VERSION 5.7 ;
  NOWIREEXTENSIONATPIN ON ;
  DIVIDERCHAR "/" ;
  BUSBITCHARS "[]" ;
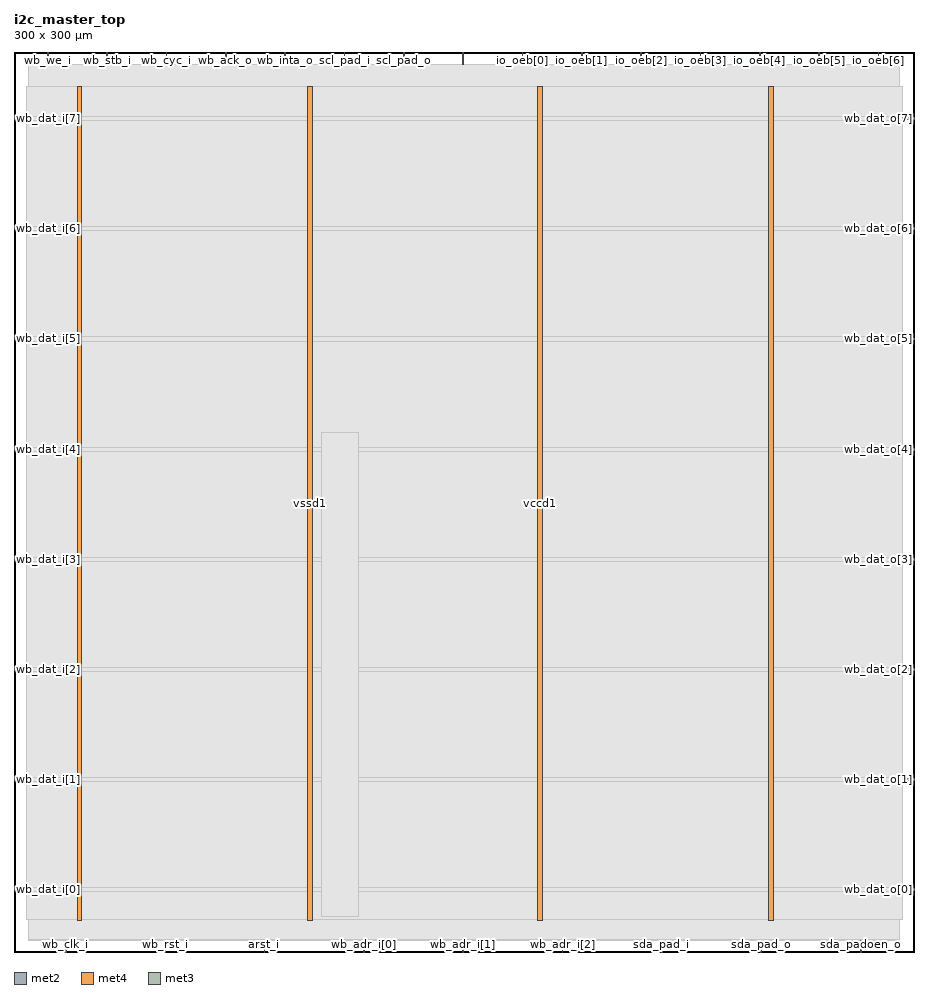
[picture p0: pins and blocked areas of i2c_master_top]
MACRO i2c_master_top
  CLASS BLOCK ;
  FOREIGN i2c_master_top ;
  ORIGIN 0.000 0.000 ;
  SIZE 300.000 BY 300.000 ;
  PIN arst_i
    DIRECTION INPUT ;
    USE SIGNAL ;
    ANTENNAGATEAREA 0.852000 ;
    PORT
      LAYER met2 ;
        RECT 83.350 0.000 83.630 4.000 ;
    END
  END arst_i
  PIN io_oeb[0]
    DIRECTION OUTPUT TRISTATE ;
    USE SIGNAL ;
    PORT
      LAYER met2 ;
        RECT 169.370 296.000 169.650 300.000 ;
    END
  END io_oeb[0]
  PIN io_oeb[1]
    DIRECTION OUTPUT TRISTATE ;
    USE SIGNAL ;
    PORT
      LAYER met2 ;
        RECT 189.150 296.000 189.430 300.000 ;
    END
  END io_oeb[1]
  PIN io_oeb[2]
    DIRECTION OUTPUT TRISTATE ;
    USE SIGNAL ;
    PORT
      LAYER met2 ;
        RECT 208.930 296.000 209.210 300.000 ;
    END
  END io_oeb[2]
  PIN io_oeb[3]
    DIRECTION OUTPUT TRISTATE ;
    USE SIGNAL ;
    PORT
      LAYER met2 ;
        RECT 228.710 296.000 228.990 300.000 ;
    END
  END io_oeb[3]
  PIN io_oeb[4]
    DIRECTION OUTPUT TRISTATE ;
    USE SIGNAL ;
    PORT
      LAYER met2 ;
        RECT 248.490 296.000 248.770 300.000 ;
    END
  END io_oeb[4]
  PIN io_oeb[5]
    DIRECTION OUTPUT TRISTATE ;
    USE SIGNAL ;
    PORT
      LAYER met2 ;
        RECT 268.270 296.000 268.550 300.000 ;
    END
  END io_oeb[5]
  PIN io_oeb[6]
    DIRECTION OUTPUT TRISTATE ;
    USE SIGNAL ;
    PORT
      LAYER met2 ;
        RECT 288.050 296.000 288.330 300.000 ;
    END
  END io_oeb[6]
  PIN scl_pad_i
    DIRECTION INPUT ;
    USE SIGNAL ;
    ANTENNAGATEAREA 0.196500 ;
    PORT
      LAYER met2 ;
        RECT 110.030 296.000 110.310 300.000 ;
    END
  END scl_pad_i
  PIN scl_pad_o
    DIRECTION OUTPUT TRISTATE ;
    USE SIGNAL ;
    PORT
      LAYER met2 ;
        RECT 129.810 296.000 130.090 300.000 ;
    END
  END scl_pad_o
  PIN scl_padoen_o
    DIRECTION OUTPUT TRISTATE ;
    USE SIGNAL ;
    ANTENNADIFFAREA 0.340600 ;
    PORT
      LAYER met2 ;
        RECT 149.590 296.000 149.870 300.000 ;
    END
  END scl_padoen_o
  PIN sda_pad_i
    DIRECTION INPUT ;
    USE SIGNAL ;
    ANTENNAGATEAREA 0.196500 ;
    PORT
      LAYER met2 ;
        RECT 215.830 0.000 216.110 4.000 ;
    END
  END sda_pad_i
  PIN sda_pad_o
    DIRECTION OUTPUT TRISTATE ;
    USE SIGNAL ;
    PORT
      LAYER met2 ;
        RECT 248.950 0.000 249.230 4.000 ;
    END
  END sda_pad_o
  PIN sda_padoen_o
    DIRECTION OUTPUT TRISTATE ;
    USE SIGNAL ;
    ANTENNADIFFAREA 0.340600 ;
    PORT
      LAYER met2 ;
        RECT 282.070 0.000 282.350 4.000 ;
    END
  END sda_padoen_o
  PIN vccd1
    DIRECTION INOUT ;
    USE POWER ;
    PORT
      LAYER met4 ;
        RECT 21.040 10.640 22.640 288.560 ;
    END
    PORT
      LAYER met4 ;
        RECT 174.640 10.640 176.240 288.560 ;
    END
  END vccd1
  PIN vssd1
    DIRECTION INOUT ;
    USE GROUND ;
    PORT
      LAYER met4 ;
        RECT 97.840 10.640 99.440 288.560 ;
    END
    PORT
      LAYER met4 ;
        RECT 251.440 10.640 253.040 288.560 ;
    END
  END vssd1
  PIN wb_ack_o
    DIRECTION OUTPUT TRISTATE ;
    USE SIGNAL ;
    ANTENNADIFFAREA 0.340600 ;
    PORT
      LAYER met2 ;
        RECT 70.470 296.000 70.750 300.000 ;
    END
  END wb_ack_o
  PIN wb_adr_i[0]
    DIRECTION INPUT ;
    USE SIGNAL ;
    ANTENNAGATEAREA 0.159000 ;
    PORT
      LAYER met2 ;
        RECT 116.470 0.000 116.750 4.000 ;
    END
  END wb_adr_i[0]
  PIN wb_adr_i[1]
    DIRECTION INPUT ;
    USE SIGNAL ;
    ANTENNAGATEAREA 0.213000 ;
    PORT
      LAYER met2 ;
        RECT 149.590 0.000 149.870 4.000 ;
    END
  END wb_adr_i[1]
  PIN wb_adr_i[2]
    DIRECTION INPUT ;
    USE SIGNAL ;
    ANTENNAGATEAREA 0.159000 ;
    PORT
      LAYER met2 ;
        RECT 182.710 0.000 182.990 4.000 ;
    END
  END wb_adr_i[2]
  PIN wb_clk_i
    DIRECTION INPUT ;
    USE SIGNAL ;
    ANTENNAGATEAREA 0.852000 ;
    PORT
      LAYER met2 ;
        RECT 17.110 0.000 17.390 4.000 ;
    END
  END wb_clk_i
  PIN wb_cyc_i
    DIRECTION INPUT ;
    USE SIGNAL ;
    ANTENNAGATEAREA 0.196500 ;
    PORT
      LAYER met2 ;
        RECT 50.690 296.000 50.970 300.000 ;
    END
  END wb_cyc_i
  PIN wb_dat_i[0]
    DIRECTION INPUT ;
    USE SIGNAL ;
    ANTENNAGATEAREA 0.159000 ;
    PORT
      LAYER met3 ;
        RECT 0.000 20.440 4.000 21.040 ;
    END
  END wb_dat_i[0]
  PIN wb_dat_i[1]
    DIRECTION INPUT ;
    USE SIGNAL ;
    ANTENNAGATEAREA 0.213000 ;
    PORT
      LAYER met3 ;
        RECT 0.000 57.160 4.000 57.760 ;
    END
  END wb_dat_i[1]
  PIN wb_dat_i[2]
    DIRECTION INPUT ;
    USE SIGNAL ;
    ANTENNAGATEAREA 0.213000 ;
    PORT
      LAYER met3 ;
        RECT 0.000 93.880 4.000 94.480 ;
    END
  END wb_dat_i[2]
  PIN wb_dat_i[3]
    DIRECTION INPUT ;
    USE SIGNAL ;
    ANTENNAGATEAREA 0.213000 ;
    PORT
      LAYER met3 ;
        RECT 0.000 130.600 4.000 131.200 ;
    END
  END wb_dat_i[3]
  PIN wb_dat_i[4]
    DIRECTION INPUT ;
    USE SIGNAL ;
    ANTENNAGATEAREA 0.213000 ;
    PORT
      LAYER met3 ;
        RECT 0.000 167.320 4.000 167.920 ;
    END
  END wb_dat_i[4]
  PIN wb_dat_i[5]
    DIRECTION INPUT ;
    USE SIGNAL ;
    ANTENNAGATEAREA 0.159000 ;
    PORT
      LAYER met3 ;
        RECT 0.000 204.040 4.000 204.640 ;
    END
  END wb_dat_i[5]
  PIN wb_dat_i[6]
    DIRECTION INPUT ;
    USE SIGNAL ;
    ANTENNAGATEAREA 0.159000 ;
    PORT
      LAYER met3 ;
        RECT 0.000 240.760 4.000 241.360 ;
    END
  END wb_dat_i[6]
  PIN wb_dat_i[7]
    DIRECTION INPUT ;
    USE SIGNAL ;
    ANTENNAGATEAREA 0.159000 ;
    PORT
      LAYER met3 ;
        RECT 0.000 277.480 4.000 278.080 ;
    END
  END wb_dat_i[7]
  PIN wb_dat_o[0]
    DIRECTION OUTPUT TRISTATE ;
    USE SIGNAL ;
    ANTENNADIFFAREA 0.340600 ;
    PORT
      LAYER met3 ;
        RECT 296.000 20.440 300.000 21.040 ;
    END
  END wb_dat_o[0]
  PIN wb_dat_o[1]
    DIRECTION OUTPUT TRISTATE ;
    USE SIGNAL ;
    ANTENNADIFFAREA 0.340600 ;
    PORT
      LAYER met3 ;
        RECT 296.000 57.160 300.000 57.760 ;
    END
  END wb_dat_o[1]
  PIN wb_dat_o[2]
    DIRECTION OUTPUT TRISTATE ;
    USE SIGNAL ;
    ANTENNADIFFAREA 0.340600 ;
    PORT
      LAYER met3 ;
        RECT 296.000 93.880 300.000 94.480 ;
    END
  END wb_dat_o[2]
  PIN wb_dat_o[3]
    DIRECTION OUTPUT TRISTATE ;
    USE SIGNAL ;
    ANTENNADIFFAREA 0.340600 ;
    PORT
      LAYER met3 ;
        RECT 296.000 130.600 300.000 131.200 ;
    END
  END wb_dat_o[3]
  PIN wb_dat_o[4]
    DIRECTION OUTPUT TRISTATE ;
    USE SIGNAL ;
    ANTENNADIFFAREA 0.340600 ;
    PORT
      LAYER met3 ;
        RECT 296.000 167.320 300.000 167.920 ;
    END
  END wb_dat_o[4]
  PIN wb_dat_o[5]
    DIRECTION OUTPUT TRISTATE ;
    USE SIGNAL ;
    ANTENNADIFFAREA 0.340600 ;
    PORT
      LAYER met3 ;
        RECT 296.000 204.040 300.000 204.640 ;
    END
  END wb_dat_o[5]
  PIN wb_dat_o[6]
    DIRECTION OUTPUT TRISTATE ;
    USE SIGNAL ;
    ANTENNADIFFAREA 0.340600 ;
    PORT
      LAYER met3 ;
        RECT 296.000 240.760 300.000 241.360 ;
    END
  END wb_dat_o[6]
  PIN wb_dat_o[7]
    DIRECTION OUTPUT TRISTATE ;
    USE SIGNAL ;
    ANTENNADIFFAREA 0.340600 ;
    PORT
      LAYER met3 ;
        RECT 296.000 277.480 300.000 278.080 ;
    END
  END wb_dat_o[7]
  PIN wb_inta_o
    DIRECTION OUTPUT TRISTATE ;
    USE SIGNAL ;
    ANTENNADIFFAREA 0.340600 ;
    PORT
      LAYER met2 ;
        RECT 90.250 296.000 90.530 300.000 ;
    END
  END wb_inta_o
  PIN wb_rst_i
    DIRECTION INPUT ;
    USE SIGNAL ;
    ANTENNAGATEAREA 0.213000 ;
    PORT
      LAYER met2 ;
        RECT 50.230 0.000 50.510 4.000 ;
    END
  END wb_rst_i
  PIN wb_stb_i
    DIRECTION INPUT ;
    USE SIGNAL ;
    ANTENNAGATEAREA 0.196500 ;
    PORT
      LAYER met2 ;
        RECT 30.910 296.000 31.190 300.000 ;
    END
  END wb_stb_i
  PIN wb_we_i
    DIRECTION INPUT ;
    USE SIGNAL ;
    ANTENNAGATEAREA 0.159000 ;
    PORT
      LAYER met2 ;
        RECT 11.130 296.000 11.410 300.000 ;
    END
  END wb_we_i
  OBS
      LAYER li1 ;
        RECT 5.520 10.795 294.400 288.405 ;
      LAYER met1 ;
        RECT 4.670 10.640 295.250 288.560 ;
      LAYER met2 ;
        RECT 4.690 295.720 10.850 296.000 ;
        RECT 11.690 295.720 30.630 296.000 ;
        RECT 31.470 295.720 50.410 296.000 ;
        RECT 51.250 295.720 70.190 296.000 ;
        RECT 71.030 295.720 89.970 296.000 ;
        RECT 90.810 295.720 109.750 296.000 ;
        RECT 110.590 295.720 129.530 296.000 ;
        RECT 130.370 295.720 149.310 296.000 ;
        RECT 150.150 295.720 169.090 296.000 ;
        RECT 169.930 295.720 188.870 296.000 ;
        RECT 189.710 295.720 208.650 296.000 ;
        RECT 209.490 295.720 228.430 296.000 ;
        RECT 229.270 295.720 248.210 296.000 ;
        RECT 249.050 295.720 267.990 296.000 ;
        RECT 268.830 295.720 287.770 296.000 ;
        RECT 288.610 295.720 295.230 296.000 ;
        RECT 4.690 4.280 295.230 295.720 ;
        RECT 4.690 4.000 16.830 4.280 ;
        RECT 17.670 4.000 49.950 4.280 ;
        RECT 50.790 4.000 83.070 4.280 ;
        RECT 83.910 4.000 116.190 4.280 ;
        RECT 117.030 4.000 149.310 4.280 ;
        RECT 150.150 4.000 182.430 4.280 ;
        RECT 183.270 4.000 215.550 4.280 ;
        RECT 216.390 4.000 248.670 4.280 ;
        RECT 249.510 4.000 281.790 4.280 ;
        RECT 282.630 4.000 295.230 4.280 ;
      LAYER met3 ;
        RECT 4.000 278.480 296.000 288.485 ;
        RECT 4.400 277.080 295.600 278.480 ;
        RECT 4.000 241.760 296.000 277.080 ;
        RECT 4.400 240.360 295.600 241.760 ;
        RECT 4.000 205.040 296.000 240.360 ;
        RECT 4.400 203.640 295.600 205.040 ;
        RECT 4.000 168.320 296.000 203.640 ;
        RECT 4.400 166.920 295.600 168.320 ;
        RECT 4.000 131.600 296.000 166.920 ;
        RECT 4.400 130.200 295.600 131.600 ;
        RECT 4.000 94.880 296.000 130.200 ;
        RECT 4.400 93.480 295.600 94.880 ;
        RECT 4.000 58.160 296.000 93.480 ;
        RECT 4.400 56.760 295.600 58.160 ;
        RECT 4.000 21.440 296.000 56.760 ;
        RECT 4.400 20.040 295.600 21.440 ;
        RECT 4.000 10.715 296.000 20.040 ;
      LAYER met4 ;
        RECT 102.415 11.735 114.705 173.225 ;
  END
END i2c_master_top
END LIBRARY

